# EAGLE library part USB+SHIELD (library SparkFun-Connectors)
USB+Shield USB connector with shield pins connectable

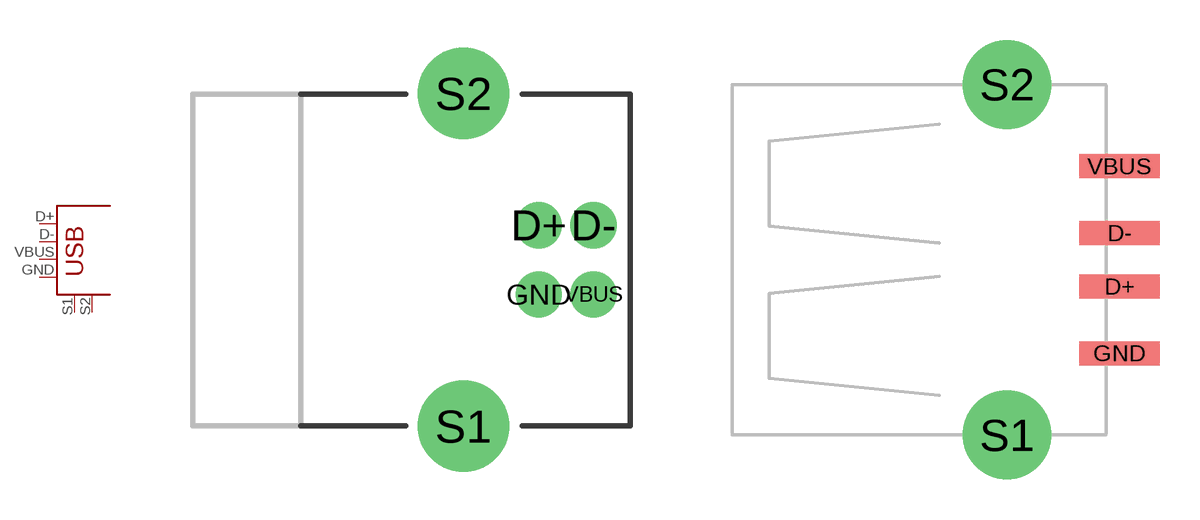
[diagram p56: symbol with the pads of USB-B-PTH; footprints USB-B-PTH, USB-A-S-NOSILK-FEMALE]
Designator prefix -

## USB+SHIELD  [USB-B-PTH]
D+  D+
D-  D-
GND  GND
S1  S1
S2  S2
VBUS  VBUS

## USB+SHIELDUSB-A-S-NOSILK-FEMALE  [USB-A-S-NOSILK-FEMALE]
Pads as for USB-B-PTH

## Footprint USB-B-PTH (pad centres in mm)
USB Series B Hole Mounted
drill 0.914 pad 1.676: D+ 0,1.25; D- 1.981,1.25; GND 0,-1.25; VBUS 1.981,-1.25
drill 2.286: S1 -2.718,-6.02; S2 -2.718,6.02

## Footprint USB-A-S-NOSILK-FEMALE (pad centres in mm)
smd 3 x 0.9: D+ 4.212,-1; D- 4.212,1; GND 4.212,-3.5; VBUS 4.212,3.5
drill 2.311: S1 0,-6.566; S2 0,6.566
